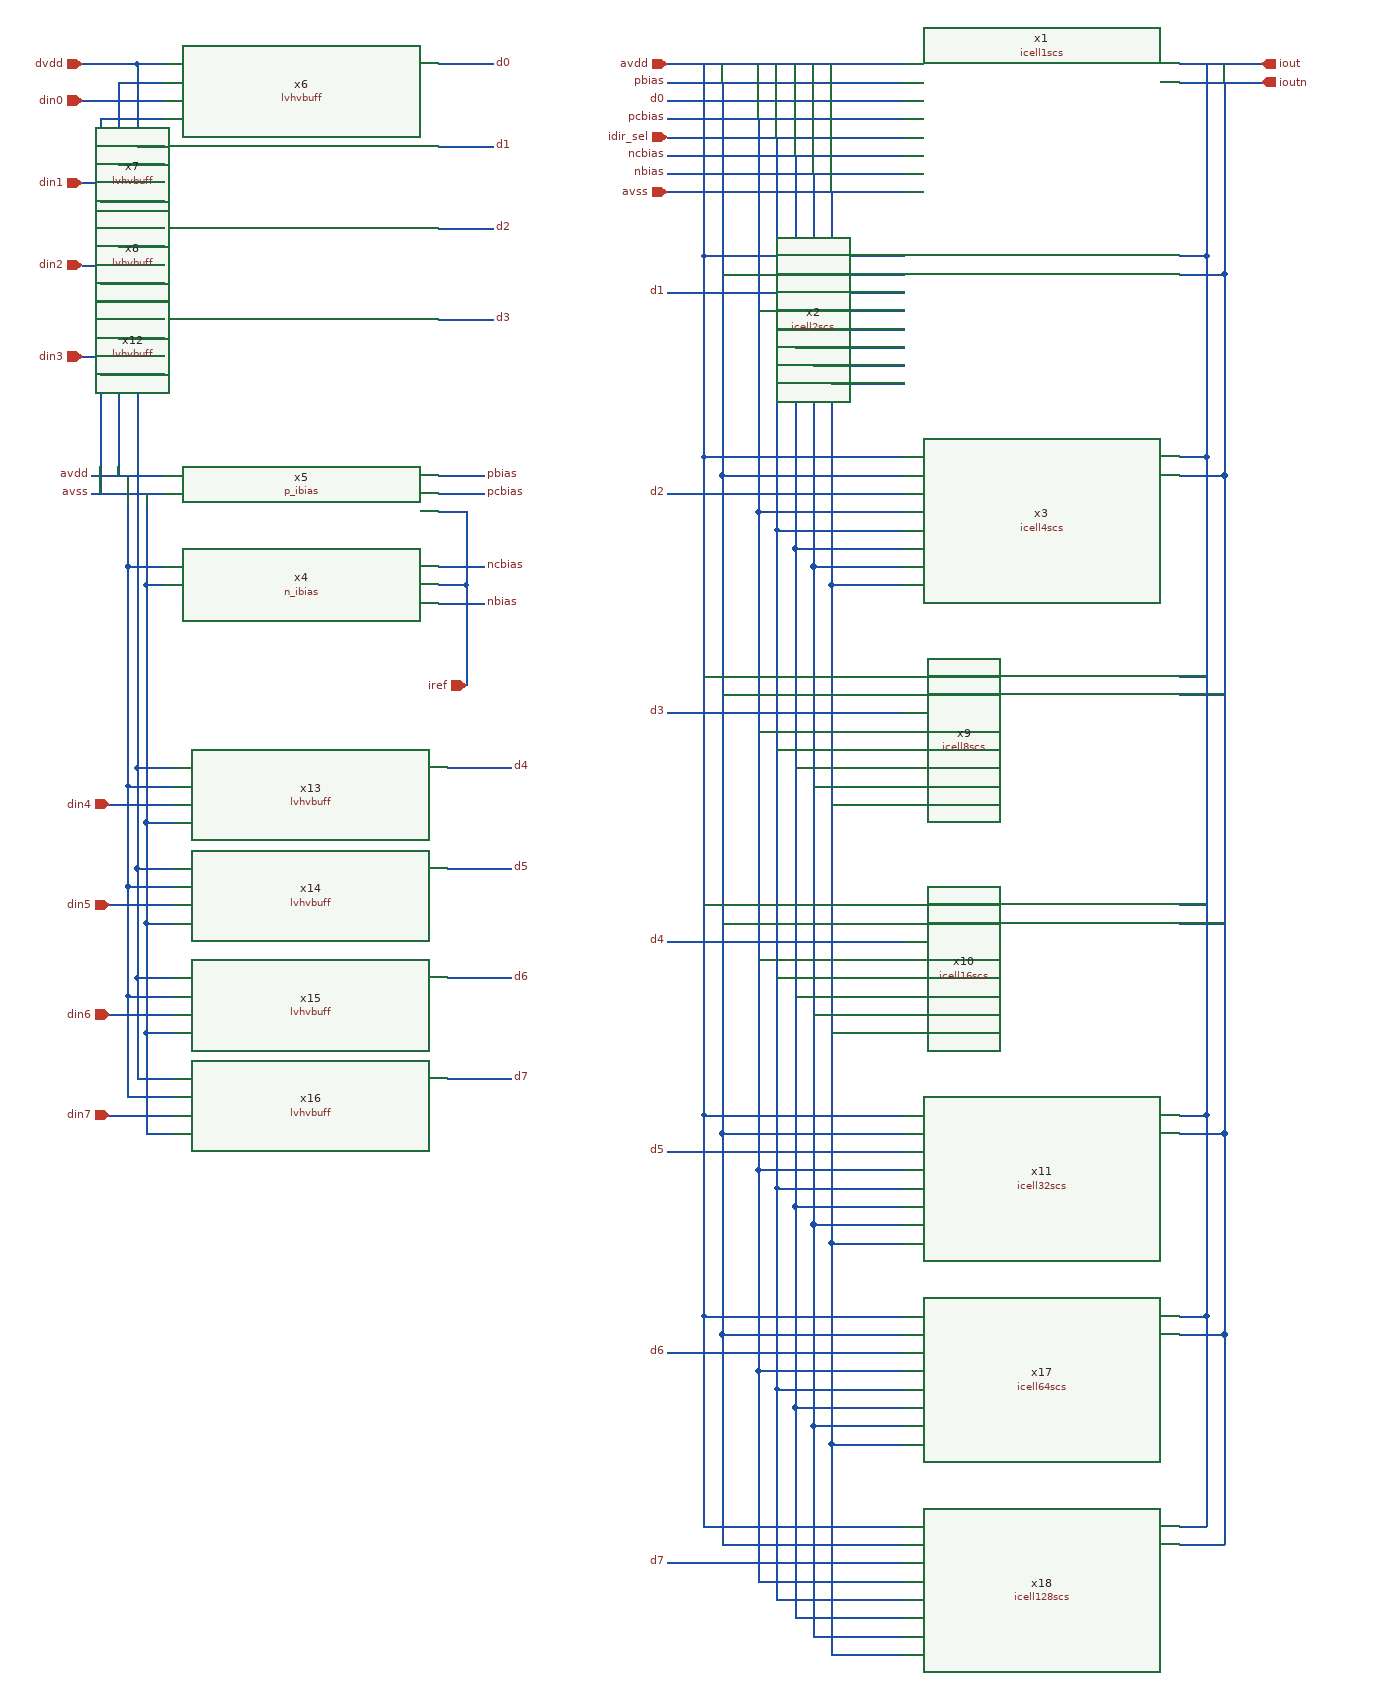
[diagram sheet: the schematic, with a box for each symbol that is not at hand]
v {xschem version=3.4.5 file_version=1.2
}
G {}
K {}
V {}
S {}
E {}
N -170 -200 -80 -200 {
lab=iout}
N -170 10 -140 10 {
lab=iout}
N -140 -200 -140 10 {
lab=iout}
N -170 230 -140 230 {
lab=iout}
N -140 10 -140 230 {
lab=iout}
N -730 -200 -470 -200 {
lab=avdd}
N -730 -180 -470 -180 {
lab=pbias}
N -730 -140 -470 -140 {
lab=pcbias}
N -730 -120 -470 -120 {
lab=idir_sel}
N -730 -100 -470 -100 {
lab=ncbias}
N -730 -80 -470 -80 {
lab=nbias}
N -730 -60 -470 -60 {
lab=avss}
N -690 -200 -690 10 {
lab=avdd}
N -690 10 -690 230 {
lab=avdd}
N -690 10 -470 10 {
lab=avdd}
N -670 -180 -670 250 {
lab=pbias}
N -630 -140 -630 290 {
lab=pcbias}
N -610 -120 -610 310 {
lab=idir_sel}
N -590 -100 -590 330 {
lab=ncbias}
N -570 -80 -570 350 {
lab=nbias}
N -550 -60 -550 370 {
lab=avss}
N -670 30 -470 30 {
lab=pbias}
N -630 70 -470 70 {
lab=pcbias}
N -610 90 -470 90 {
lab=idir_sel}
N -590 110 -470 110 {
lab=ncbias}
N -570 130 -470 130 {
lab=nbias}
N -550 150 -470 150 {
lab=avss}
N -690 230 -470 230 {
lab=avdd}
N -670 250 -470 250 {
lab=pbias}
N -630 290 -470 290 {
lab=pcbias}
N -610 310 -470 310 {
lab=idir_sel}
N -590 330 -470 330 {
lab=ncbias}
N -570 350 -470 350 {
lab=nbias}
N -550 370 -470 370 {
lab=avss}
N -1360 250 -1280 250 {
lab=avdd}
N -1360 270 -1280 270 {
lab=avss}
N -1320 350 -1280 350 {
lab=avdd}
N -1320 250 -1320 350 {
lab=avdd}
N -1300 270 -1300 370 {
lab=avss}
N -1300 370 -1280 370 {
lab=avss}
N -980 250 -930 250 {
lab=pbias}
N -980 270 -930 270 {
lab=pcbias}
N -950 290 -950 370 {
lab=iref}
N -980 370 -950 370 {
lab=iref}
N -980 350 -930 350 {
lab=ncbias}
N -980 390 -930 390 {
lab=nbias}
N -980 290 -950 290 {
lab=iref}
N -950 370 -950 420 {
lab=iref}
N -950 420 -950 480 {
lab=iref}
N -730 -160 -470 -160 {
lab=d0}
N -730 50 -470 50 {
lab=d1}
N -730 270 -470 270 {
lab=d2}
N -980 -200 -920 -200 {
lab=d0}
N -980 -110 -920 -110 {
lab=d1}
N -980 -20 -920 -20 {
lab=d2}
N -1310 -200 -1280 -200 {
lab=dvdd}
N -1370 20 -1280 20 {
lab=din2}
N -1370 -70 -1280 -70 {
lab=din1}
N -1370 -160 -1280 -160 {
lab=din0}
N -1310 -200 -1310 -20 {
lab=dvdd}
N -1310 -20 -1280 -20 {
lab=dvdd}
N -1310 -110 -1280 -110 {
lab=dvdd}
N -1370 -200 -1310 -200 {
lab=dvdd}
N -1330 -180 -1280 -180 {
lab=avdd}
N -1330 -180 -1330 250 {
lab=avdd}
N -1330 -90 -1280 -90 {
lab=avdd}
N -1330 0 -1280 0 {
lab=avdd}
N -1350 -140 -1280 -140 {
lab=avss}
N -1350 -140 -1350 270 {
lab=avss}
N -1350 -50 -1280 -50 {
lab=avss}
N -1350 40 -1280 40 {
lab=avss}
N -170 -180 -80 -180 {
lab=ioutn}
N -170 30 -120 30 {
lab=ioutn}
N -120 -180 -120 30 {
lab=ioutn}
N -170 250 -120 250 {
lab=ioutn}
N -120 30 -120 250 {
lab=ioutn}
N -550 370 -550 1090 {
lab=avss}
N -550 1090 -470 1090 {
lab=avss}
N -550 860 -470 860 {
lab=avss}
N -550 610 -470 610 {
lab=avss}
N -570 350 -570 1070 {
lab=nbias}
N -570 1070 -470 1070 {
lab=nbias}
N -570 840 -470 840 {
lab=nbias}
N -570 590 -470 590 {
lab=nbias}
N -590 330 -590 1050 {
lab=ncbias}
N -590 1050 -470 1050 {
lab=ncbias}
N -590 820 -470 820 {
lab=ncbias}
N -590 570 -470 570 {
lab=ncbias}
N -610 310 -610 1030 {
lab=idir_sel}
N -610 1030 -470 1030 {
lab=idir_sel}
N -610 800 -470 800 {
lab=idir_sel}
N -610 550 -470 550 {
lab=idir_sel}
N -630 290 -630 1010 {
lab=pcbias}
N -630 1010 -470 1010 {
lab=pcbias}
N -630 780 -470 780 {
lab=pcbias}
N -630 530 -470 530 {
lab=pcbias}
N -730 510 -470 510 {
lab=d3}
N -730 760 -470 760 {
lab=d4}
N -730 990 -470 990 {
lab=d5}
N -670 250 -670 970 {
lab=pbias}
N -670 970 -470 970 {
lab=pbias}
N -670 740 -470 740 {
lab=pbias}
N -670 490 -470 490 {
lab=pbias}
N -690 230 -690 950 {
lab=avdd}
N -690 950 -470 950 {
lab=avdd}
N -690 720 -470 720 {
lab=avdd}
N -690 470 -470 470 {
lab=avdd}
N -140 230 -140 950 {
lab=iout}
N -170 950 -140 950 {
lab=iout}
N -170 720 -140 720 {
lab=iout}
N -170 470 -140 470 {
lab=iout}
N -120 250 -120 970 {
lab=ioutn}
N -170 970 -120 970 {
lab=ioutn}
N -170 740 -120 740 {
lab=ioutn}
N -170 490 -120 490 {
lab=ioutn}
N -1310 -20 -1310 80 {
lab=dvdd}
N -1310 80 -1280 80 {
lab=dvdd}
N -1310 80 -1310 570 {
lab=dvdd}
N -1310 570 -1270 570 {
lab=dvdd}
N -1310 570 -1310 680 {
lab=dvdd}
N -1310 680 -1270 680 {
lab=dvdd}
N -1320 350 -1320 590 {
lab=avdd}
N -1320 590 -1270 590 {
lab=avdd}
N -1320 590 -1320 700 {
lab=avdd}
N -1320 700 -1270 700 {
lab=avdd}
N -1300 370 -1300 630 {
lab=avss}
N -1300 630 -1270 630 {
lab=avss}
N -1300 630 -1300 740 {
lab=avss}
N -1300 740 -1270 740 {
lab=avss}
N -1330 100 -1280 100 {
lab=avdd}
N -1350 140 -1280 140 {
lab=avss}
N -1370 120 -1280 120 {
lab=din3}
N -1340 610 -1270 610 {
lab=din4}
N -1340 720 -1270 720 {
lab=din5}
N -980 80 -920 80 {
lab=d3}
N -970 570 -900 570 {
lab=d4}
N -970 680 -900 680 {
lab=d5}
N -1310 800 -1270 800 {
lab=dvdd}
N -1310 800 -1310 910 {
lab=dvdd}
N -1310 910 -1270 910 {
lab=dvdd}
N -1320 820 -1270 820 {
lab=avdd}
N -1320 820 -1320 930 {
lab=avdd}
N -1320 930 -1270 930 {
lab=avdd}
N -1300 860 -1270 860 {
lab=avss}
N -1300 860 -1300 970 {
lab=avss}
N -1300 970 -1270 970 {
lab=avss}
N -1340 840 -1270 840 {
lab=din6}
N -1340 950 -1270 950 {
lab=din7}
N -970 800 -900 800 {
lab=d6}
N -970 910 -900 910 {
lab=d7}
N -1300 740 -1300 860 {
lab=avss}
N -1310 680 -1310 800 {
lab=dvdd}
N -1320 700 -1320 820 {
lab=avdd}
N -550 1540 -470 1540 {
lab=avss}
N -550 1310 -470 1310 {
lab=avss}
N -570 1520 -470 1520 {
lab=nbias}
N -570 1290 -470 1290 {
lab=nbias}
N -590 1500 -470 1500 {
lab=ncbias}
N -590 1270 -470 1270 {
lab=ncbias}
N -610 1480 -470 1480 {
lab=idir_sel}
N -610 1250 -470 1250 {
lab=idir_sel}
N -630 1460 -470 1460 {
lab=pcbias}
N -630 1230 -470 1230 {
lab=pcbias}
N -730 1210 -470 1210 {
lab=d6}
N -730 1440 -470 1440 {
lab=d7}
N -670 1420 -470 1420 {
lab=pbias}
N -670 1190 -470 1190 {
lab=pbias}
N -690 1400 -470 1400 {
lab=avdd}
N -690 1170 -470 1170 {
lab=avdd}
N -170 1400 -140 1400 {
lab=iout}
N -170 1170 -140 1170 {
lab=iout}
N -170 1420 -120 1420 {
lab=ioutn}
N -170 1190 -120 1190 {
lab=ioutn}
N -550 1090 -550 1310 {
lab=avss}
N -550 1310 -550 1540 {
lab=avss}
N -570 1290 -570 1520 {
lab=nbias}
N -570 1070 -570 1290 {
lab=nbias}
N -590 1050 -590 1270 {
lab=ncbias}
N -590 1270 -590 1500 {
lab=ncbias}
N -610 1250 -610 1480 {
lab=idir_sel}
N -610 1030 -610 1250 {
lab=idir_sel}
N -630 1010 -630 1230 {
lab=pcbias}
N -630 1230 -630 1460 {
lab=pcbias}
N -670 1190 -670 1420 {
lab=pbias}
N -670 970 -670 1190 {
lab=pbias}
N -690 950 -690 1170 {
lab=avdd}
N -690 1170 -690 1400 {
lab=avdd}
N -140 950 -140 1170 {
lab=iout}
N -140 1170 -140 1400 {
lab=iout}
N -120 970 -120 1190 {
lab=ioutn}
N -120 1190 -120 1420 {
lab=ioutn}
C {devices/ipin.sym} -730 -200 0 0 {name=p1 lab=avdd}
C {devices/ipin.sym} -1370 -160 0 0 {name=p3 lab=din0}
C {devices/ipin.sym} -730 -120 0 0 {name=p5 lab=idir_sel}
C {devices/ipin.sym} -730 -60 0 0 {name=p8 lab=avss}
C {devices/ipin.sym} -1370 -70 0 0 {name=p9 lab=din1}
C {devices/ipin.sym} -1370 20 0 0 {name=p10 lab=din2}
C {devices/opin.sym} -80 -200 0 0 {name=p11 lab=iout}
C {n_ibias.sym} -1130 370 0 0 {name=x4}
C {p_ibias.sym} -1130 270 0 0 {name=x5}
C {devices/lab_pin.sym} -730 -180 0 0 {name=p2 sig_type=std_logic lab=pbias}
C {devices/lab_pin.sym} -730 -140 0 0 {name=p4 sig_type=std_logic lab=pcbias}
C {devices/lab_pin.sym} -730 -100 0 0 {name=p6 sig_type=std_logic lab=ncbias}
C {devices/lab_pin.sym} -730 -80 0 0 {name=p7 sig_type=std_logic lab=nbias}
C {devices/lab_pin.sym} -930 250 0 1 {name=p12 sig_type=std_logic lab=pbias}
C {devices/lab_pin.sym} -930 270 0 1 {name=p13 sig_type=std_logic lab=pcbias}
C {devices/lab_pin.sym} -930 390 0 1 {name=p14 sig_type=std_logic lab=nbias}
C {devices/lab_pin.sym} -930 350 0 1 {name=p15 sig_type=std_logic lab=ncbias}
C {devices/lab_pin.sym} -1360 250 0 0 {name=p16 sig_type=std_logic lab=avdd}
C {devices/lab_pin.sym} -1360 270 0 0 {name=p17 sig_type=std_logic lab=avss}
C {devices/iopin.sym} -950 480 0 0 {name=p18 lab=iref}
C {lvhvbuff.sym} -1130 -170 0 0 {name=x6}
C {lvhvbuff.sym} -1130 -80 0 0 {name=x7}
C {lvhvbuff.sym} -1130 10 0 0 {name=x8}
C {devices/ipin.sym} -1370 -200 0 0 {name=p19 lab=dvdd}
C {devices/lab_pin.sym} -730 -160 0 0 {name=p20 sig_type=std_logic lab=d0}
C {devices/lab_pin.sym} -730 50 0 0 {name=p21 sig_type=std_logic lab=d1}
C {devices/lab_pin.sym} -730 270 0 0 {name=p22 sig_type=std_logic lab=d2}
C {devices/lab_pin.sym} -920 -200 0 1 {name=p23 sig_type=std_logic lab=d0}
C {devices/lab_pin.sym} -920 -110 0 1 {name=p24 sig_type=std_logic lab=d1}
C {devices/lab_pin.sym} -920 -20 0 1 {name=p25 sig_type=std_logic lab=d2}
C {icell1scs.sym} -320 -130 0 0 {name=x1}
C {icell2scs.sym} -320 80 0 0 {name=x2}
C {icell4scs.sym} -320 300 0 0 {name=x3}
C {devices/opin.sym} -80 -180 0 0 {name=p26 lab=ioutn}
C {icell8scs.sym} -320 540 0 0 {name=x9}
C {icell16scs.sym} -320 790 0 0 {name=x10}
C {icell32scs.sym} -320 1020 0 0 {name=x11}
C {devices/lab_pin.sym} -730 510 0 0 {name=p27 sig_type=std_logic lab=d3}
C {devices/lab_pin.sym} -730 760 0 0 {name=p28 sig_type=std_logic lab=d4}
C {devices/lab_pin.sym} -730 990 0 0 {name=p29 sig_type=std_logic lab=d5}
C {lvhvbuff.sym} -1130 110 0 0 {name=x12}
C {lvhvbuff.sym} -1120 600 0 0 {name=x13}
C {lvhvbuff.sym} -1120 710 0 0 {name=x14}
C {devices/ipin.sym} -1370 120 0 0 {name=p30 lab=din3}
C {devices/ipin.sym} -1340 610 0 0 {name=p31 lab=din4}
C {devices/ipin.sym} -1340 720 0 0 {name=p32 lab=din5}
C {devices/lab_pin.sym} -920 80 0 1 {name=p33 sig_type=std_logic lab=d3}
C {devices/lab_pin.sym} -900 570 0 1 {name=p34 sig_type=std_logic lab=d4}
C {devices/lab_pin.sym} -900 680 0 1 {name=p35 sig_type=std_logic lab=d5}
C {lvhvbuff.sym} -1120 830 0 0 {name=x15}
C {lvhvbuff.sym} -1120 940 0 0 {name=x16}
C {devices/ipin.sym} -1340 840 0 0 {name=p36 lab=din6}
C {devices/ipin.sym} -1340 950 0 0 {name=p37 lab=din7}
C {devices/lab_pin.sym} -900 800 0 1 {name=p38 sig_type=std_logic lab=d6}
C {devices/lab_pin.sym} -900 910 0 1 {name=p39 sig_type=std_logic lab=d7}
C {devices/lab_pin.sym} -730 1210 0 0 {name=p40 sig_type=std_logic lab=d6}
C {devices/lab_pin.sym} -730 1440 0 0 {name=p41 sig_type=std_logic lab=d7}
C {icell64scs.sym} -320 1240 0 0 {name=x17}
C {icell128scs.sym} -320 1470 0 0 {name=x18}
